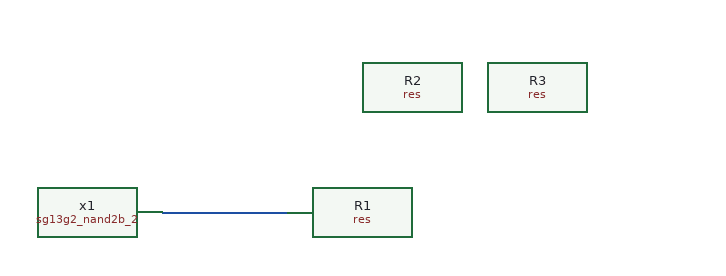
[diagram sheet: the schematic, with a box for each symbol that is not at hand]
v {xschem version=3.4.8RC file_version=1.3}
G {}
K {}
V {}
S {}
F {}
E {}
N 0 100 100 100 {lab=a\}b}
C {sg13g2_stdcell/sg13g2_nand2b_2.sym} 0 0 0 0 {name=x1 value="@prefix\\\\nand2b_2" prefix=sg13g2_}
C {res.sym} 100 0 0 0 {name=R1 value="\}"}
C {res.sym} 200 0 0 0 {name=R2 value=1k}
C {res.sym} 300 0 0 0 {name=R3 value="a;b"}
